VERSION 5.8 ;
BUSBITCHARS "[]" ;
DIVIDERCHAR "/" ;
UNITS
    DATABASE MICRONS 1000 ;
END UNITS

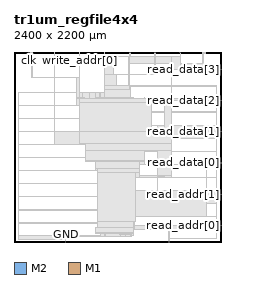
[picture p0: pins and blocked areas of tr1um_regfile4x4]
MACRO tr1um_regfile4x4
  FOREIGN tr1um_regfile4x4 0 0 ;
  CLASS BLOCK ;
  SIZE 2400 BY 2200 ;
  PIN GND
    DIRECTION INOUT ;
    USE SIGNAL ;
    PORT
      LAYER M2 ;
        RECT  593.7 0 599.7 6 ;
    END
  END GND
  PIN VDD
    DIRECTION INOUT ;
    USE SIGNAL ;
    PORT
      LAYER M2 ;
        RECT  1792.5 0 1798.5 6 ;
    END
  END VDD
  PIN clk
    DIRECTION INPUT ;
    USE SIGNAL ;
    PORT
      LAYER M2 ;
        RECT  172.5 2194 178.5 2200 ;
    END
  END clk
  PIN read_addr[0]
    DIRECTION INPUT ;
    USE SIGNAL ;
    PORT
      LAYER M1 ;
        RECT  2396.4 189.9 2400 193.5 ;
    END
  END read_addr[0]
  PIN read_addr[1]
    DIRECTION INPUT ;
    USE SIGNAL ;
    PORT
      LAYER M1 ;
        RECT  2396.4 551.7 2400 555.3 ;
    END
  END read_addr[1]
  PIN read_data[0]
    DIRECTION OUTPUT ;
    USE SIGNAL ;
    PORT
      LAYER M1 ;
        RECT  2396.4 913.5 2400 917.1 ;
    END
  END read_data[0]
  PIN read_data[1]
    DIRECTION OUTPUT ;
    USE SIGNAL ;
    PORT
      LAYER M1 ;
        RECT  2396.4 1275.3 2400 1278.9 ;
    END
  END read_data[1]
  PIN read_data[2]
    DIRECTION OUTPUT ;
    USE SIGNAL ;
    PORT
      LAYER M1 ;
        RECT  2396.4 1637.1 2400 1640.7 ;
    END
  END read_data[2]
  PIN read_data[3]
    DIRECTION OUTPUT ;
    USE SIGNAL ;
    PORT
      LAYER M1 ;
        RECT  2396.4 1998.9 2400 2002.5 ;
    END
  END read_data[3]
  PIN write_addr[0]
    DIRECTION INPUT ;
    USE SIGNAL ;
    PORT
      LAYER M2 ;
        RECT  755.7 2194 761.7 2200 ;
    END
  END write_addr[0]
  PIN write_addr[1]
    DIRECTION INPUT ;
    USE SIGNAL ;
    PORT
      LAYER M2 ;
        RECT  1047.3 2194 1053.3 2200 ;
    END
  END write_addr[1]
  PIN write_data[0]
    DIRECTION INPUT ;
    USE SIGNAL ;
    PORT
      LAYER M2 ;
        RECT  1338.9 2194 1344.9 2200 ;
    END
  END write_data[0]
  PIN write_data[1]
    DIRECTION INPUT ;
    USE SIGNAL ;
    PORT
      LAYER M2 ;
        RECT  1630.5 2194 1636.5 2200 ;
    END
  END write_data[1]
  PIN write_data[2]
    DIRECTION INPUT ;
    USE SIGNAL ;
    PORT
      LAYER M2 ;
        RECT  1922.1 2194 1928.1 2200 ;
    END
  END write_data[2]
  PIN write_data[3]
    DIRECTION INPUT ;
    USE SIGNAL ;
    PORT
      LAYER M2 ;
        RECT  2213.7 2194 2219.7 2200 ;
    END
  END write_data[3]
  PIN write_enable
    DIRECTION INPUT ;
    USE SIGNAL ;
    PORT
      LAYER M2 ;
        RECT  464.1 2194 470.1 2200 ;
    END
  END write_enable
  OBS
    LAYER M1 ;
     RECT  53.1 29.1 54.9 1732.7 ;
     RECT  54.9 1126.1 466.2 1127.9 ;
     RECT  54.9 1277.3 466.2 1279.1 ;
     RECT  54.9 29.1 595 69.5 ;
     RECT  595 28.3 598.4 69.5 ;
     RECT  54.9 1579.7 725.4 1581.5 ;
     RECT  54.9 1730.9 725.4 1732.7 ;
     RECT  207 1902.6 727.2 1904.4 ;
     RECT  54.9 1428.5 792.3 1430.3 ;
     RECT  725.4 1579.7 792.3 1732.7 ;
     RECT  54.9 974.9 828 976.7 ;
     RECT  466.2 1126.1 869.3 1279.1 ;
     RECT  792.3 1428.5 869.3 1732.7 ;
     RECT  54.9 823.7 938 825.5 ;
     RECT  828 930.6 938 976.7 ;
     RECT  938 823.7 940.8 976.7 ;
     RECT  869.3 1126.1 940.8 1732.7 ;
     RECT  54.9 521.3 984.6 523.1 ;
     RECT  940.8 823.7 995.4 1732.7 ;
     RECT  54.9 218.9 995.8 220.7 ;
     RECT  54.9 370.1 995.8 371.9 ;
     RECT  984.6 482.4 995.8 523.1 ;
     RECT  54.9 672.5 995.8 674.3 ;
     RECT  995.4 817.2 995.8 1732.7 ;
     RECT  598.4 67.7 1004 69.5 ;
     RECT  995.8 218.9 1004 1732.7 ;
     RECT  1004 67.7 1049.5 1732.7 ;
     RECT  1049.5 67.7 1060.4 1807.7 ;
     RECT  1060.4 67.7 1291.6 1809.6 ;
     RECT  1173.6 2145.6 1324.8 2147.4 ;
     RECT  1324.8 2064.6 1335.6 2147.4 ;
     RECT  1291.6 67.7 1345.9 1807.7 ;
     RECT  1345.9 67.7 1356.8 1672.2 ;
     RECT  1356.8 75.6 1380.6 1672.2 ;
     RECT  1380.6 75.6 1385 1666.8 ;
     RECT  1385 142.7 1393.3 1666.8 ;
     RECT  1393.3 747.5 1448.3 1666.8 ;
     RECT  1448.3 747.5 1450.8 943.2 ;
     RECT  1450.8 747.5 1456.2 937.8 ;
     RECT  1448.3 1049.9 1510.2 1666.8 ;
     RECT  1456.2 898.7 1515.6 937.8 ;
     RECT  1510.2 1049.9 1519.8 1658.4 ;
     RECT  1519.8 1049.9 1526.4 1202.9 ;
     RECT  1526.4 1049.9 1591.2 1056.6 ;
     RECT  1519.8 1352.3 1596.8 1658.4 ;
     RECT  1184.4 1940.4 1634.4 1942.2 ;
     RECT  1526.4 1201.1 1659.6 1202.9 ;
     RECT  1596.8 1352.3 1659.6 1354.1 ;
     RECT  1596.8 1654.7 1740.6 1656.5 ;
     RECT  1393.3 142.7 1793.8 192.6 ;
     RECT  1793.8 43.3 1797.2 192.6 ;
     RECT  1335.6 2064.6 1821.6 2152.8 ;
     RECT  1456.2 747.5 1823.4 770.4 ;
     RECT  1821.6 1999.8 1926 2152.8 ;
     RECT  1926 1999.8 2190.6 2066.4 ;
     RECT  1515.6 898.7 2226.6 900.5 ;
     RECT  1393.3 293.9 2228.4 598.1 ;
     RECT  1797.2 44.1 2339.1 45.9 ;
     RECT  1797.2 142.7 2339.1 192.6 ;
     RECT  2228.4 293.9 2339.1 295.7 ;
     RECT  2228.4 445.1 2339.1 598.1 ;
     RECT  1823.4 747.5 2339.1 749.3 ;
     RECT  2226.6 898.7 2339.1 916.2 ;
     RECT  1591.2 1049.9 2339.1 1051.7 ;
     RECT  1659.6 1201.1 2339.1 1354.1 ;
     RECT  1596.8 1503.5 2339.1 1505.3 ;
     RECT  1740.6 1638 2339.1 1656.5 ;
     RECT  1345.9 1805.9 2339.1 1807.7 ;
     RECT  2339.1 44.1 2340.9 1807.7 ;
     RECT  2340.9 190.8 2398.2 192.6 ;
     RECT  2340.9 552.6 2398.2 554.4 ;
     RECT  2340.9 914.4 2398.2 916.2 ;
     RECT  2340.9 1276.2 2398.2 1278 ;
     RECT  2340.9 1638 2398.2 1639.8 ;
     RECT  2190.6 1999.8 2398.2 2001.6 ;
    LAYER M2 ;
     RECT  595.2 3 598.2 28.3 ;
     RECT  595 28.3 598.4 31.7 ;
     RECT  1794 3 1797 43.3 ;
     RECT  1793.8 43.3 1797.2 46.7 ;
     RECT  1230 77.2 1233.4 91.7 ;
     RECT  1227.3 91.7 1305.3 91.9 ;
     RECT  1221.6 91.9 1338 95.7 ;
     RECT  1221.6 95.7 1374.3 97.2 ;
     RECT  1221.6 97.2 1374.4 102.7 ;
     RECT  1020 102.7 1379.9 102.9 ;
     RECT  946.2 102.9 1382.5 111.4 ;
     RECT  946.2 111.4 1381.2 163.5 ;
     RECT  2334 190.2 2347.8 193.2 ;
     RECT  967.8 163.5 1381.2 243.1 ;
     RECT  2226 363 2229 514.2 ;
     RECT  2226 514.2 2347.8 517.2 ;
     RECT  2344.8 517.2 2347.8 555 ;
     RECT  1659 579 1662 757.2 ;
     RECT  1659 757.2 1743 768 ;
     RECT  967.8 243.1 1408.2 805.8 ;
     RECT  967.8 805.8 1456.8 853.2 ;
     RECT  954 853.2 1456.8 853.4 ;
     RECT  951.6 853.4 1456.8 854.4 ;
     RECT  2226 517.2 2229 913.8 ;
     RECT  2226 913.8 2347.8 916.8 ;
     RECT  940.8 854.4 1456.8 935.4 ;
     RECT  827.4 930 830.4 940.8 ;
     RECT  940.8 935.4 1516.2 940.8 ;
     RECT  827.4 940.8 1516.2 1054.2 ;
     RECT  1659 768 1824 1054.2 ;
     RECT  827.4 1054.2 1824 1140.6 ;
     RECT  757.2 1140.6 1824 1278.6 ;
     RECT  2334 1275.6 2347.8 1278.6 ;
     RECT  757.2 1278.6 1591.8 1616.4 ;
     RECT  757.2 1616.4 1591.7 1618.1 ;
     RECT  1740 1278.6 1824 1640.4 ;
     RECT  2334 1637.4 2347.8 1640.4 ;
     RECT  757.2 1618.1 1553.2 1658.4 ;
     RECT  757.2 1658.4 814.2 1664.4 ;
     RECT  951.6 1658.4 1381.2 1667.4 ;
     RECT  1507.8 1658.4 1510.8 1667.4 ;
     RECT  724.8 1664.4 814.2 1672.8 ;
     RECT  951.6 1667.4 1343.4 1672.8 ;
     RECT  1048.8 1672.8 1343.4 1764.6 ;
     RECT  1048.8 1764.6 1338 1809.6 ;
     RECT  724.8 1672.8 760.2 1905 ;
     RECT  1048.8 1809.6 1186.8 1942.8 ;
     RECT  1821 1640.4 1824 2002.2 ;
     RECT  1324.2 1809.6 1338 2067 ;
     RECT  1048.8 1942.8 1154.4 2104.5 ;
     RECT  1048.8 2104.5 1176 2107.5 ;
     RECT  1335 2067 1338 2145 ;
     RECT  1173 2107.5 1176 2148 ;
     RECT  1335 2145 1343.4 2153.4 ;
     RECT  206.4 1902 209.4 2188.2 ;
     RECT  2188.2 2064 2191.2 2188.2 ;
     RECT  174 2188.2 209.4 2197 ;
     RECT  465.6 1210.8 468.6 2197 ;
     RECT  757.2 1905 760.2 2197 ;
     RECT  1048.8 2107.5 1051.8 2197 ;
     RECT  1340.4 2153.4 1343.4 2197 ;
     RECT  1632 1939.8 1635 2197 ;
     RECT  1923.6 2150.4 1926.6 2197 ;
     RECT  2188.2 2188.2 2218.2 2197 ;
     RECT  190.2 2197 209.4 2198.5 ;
     RECT  2188.2 2197 2202 2198.5 ;
  END
END tr1um_regfile4x4
END LIBRARY
